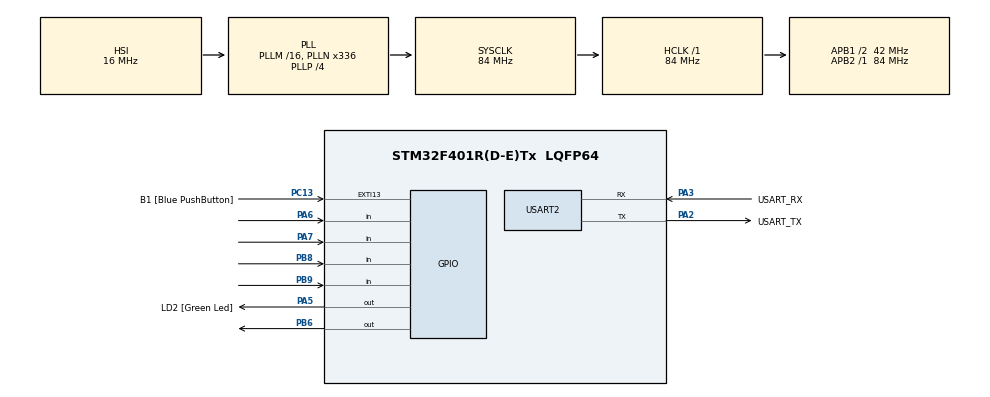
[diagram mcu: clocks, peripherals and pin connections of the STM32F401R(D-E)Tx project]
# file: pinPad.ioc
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Mcu.Family=STM32F4
Mcu.Name=STM32F401R(D-E)Tx
Mcu.Package=LQFP64
NVIC.PriorityGroup=NVIC_PRIORITYGROUP_0
PA13.GPIO_Label=TMS
PA13.Mode=Serial_Wire
PA13.Signal=SYS_JTMS-SWDIO
PA14.GPIO_Label=TCK
PA14.Mode=Serial_Wire
PA14.Signal=SYS_JTCK-SWCLK
PA2.GPIO_Label=USART_TX
PA2.GPIO_Mode=GPIO_MODE_AF_PP
PA2.GPIO_PuPd=GPIO_NOPULL
PA2.GPIO_Speed=GPIO_SPEED_FREQ_LOW
PA2.Mode=Asynchronous
PA2.Signal=USART2_TX
PA3.GPIO_Label=USART_RX
PA3.GPIO_Mode=GPIO_MODE_AF_PP
PA3.GPIO_PuPd=GPIO_NOPULL
PA3.GPIO_Speed=GPIO_SPEED_FREQ_LOW
PA3.Mode=Asynchronous
PA3.Signal=USART2_RX
PA5.GPIO_Label=LD2 [Green Led]
PA5.GPIO_Mode=GPIO_MODE_OUTPUT_PP
PA5.GPIO_PuPd=GPIO_NOPULL
PA5.GPIO_Speed=GPIO_SPEED_FREQ_LOW
PA5.Signal=GPIO_Output
PA6.GPIO_PuPd=GPIO_PULLDOWN
PA6.Signal=GPIO_Input
PA7.GPIO_PuPd=GPIO_PULLDOWN
PA7.Signal=GPIO_Input
PB3.GPIO_Label=SWO
PB3.Signal=SYS_JTDO-SWO
PB6.Signal=GPIO_Output
PB8.GPIO_PuPd=GPIO_PULLDOWN
PB8.Signal=GPIO_Input
PB9.GPIO_PuPd=GPIO_PULLDOWN
PB9.Signal=GPIO_Input
PC13-ANTI_TAMP.GPIO_Label=B1 [Blue PushButton]
PC13-ANTI_TAMP.GPIO_ModeDefaultEXTI=GPIO_MODE_IT_FALLING
PC13-ANTI_TAMP.GPIO_PuPd=GPIO_NOPULL
PC13-ANTI_TAMP.Signal=GPXTI13
PC14-OSC32_IN.Mode=LSE-External-Oscillator
PC14-OSC32_IN.Signal=RCC_OSC32_IN
PC15-OSC32_OUT.Mode=LSE-External-Oscillator
PC15-OSC32_OUT.Signal=RCC_OSC32_OUT
PH0\ -\ OSC_IN.Mode=HSE-External-Clock-Source
PH0\ -\ OSC_IN.Signal=RCC_OSC_IN
PH1\ -\ OSC_OUT.Mode=HSE-External-Clock-Source
PH1\ -\ OSC_OUT.Signal=RCC_OSC_OUT
ProjectManager.HeapSize=0x200
ProjectManager.StackSize=0x400
ProjectManager.TargetToolchain=STM32CubeIDE
RCC.48MHZClocksFreq_Value=48000000
RCC.AHBFreq_Value=84000000
RCC.APB1CLKDivider=RCC_HCLK_DIV2
RCC.APB1Freq_Value=42000000
RCC.APB1TimFreq_Value=84000000
RCC.APB2Freq_Value=84000000
RCC.APB2TimFreq_Value=84000000
RCC.CortexFreq_Value=84000000
RCC.HCLKFreq_Value=84000000
RCC.HSE_VALUE=8000000
RCC.HSI_VALUE=16000000
RCC.PLLN=336
RCC.PLLP=RCC_PLLP_DIV4
RCC.PLLQ=7
RCC.SYSCLKFreq_VALUE=84000000
RCC.SYSCLKSource=RCC_SYSCLKSOURCE_PLLCLK
RCC.VCOOutputFreq_Value=336000000
USART2.VirtualMode=VM_ASYNC
board=NUCLEO-F401RE

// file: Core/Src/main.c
/* USER CODE BEGIN Header */
/**
  ******************************************************************************
  * @file           : main.c
  * @brief          : Main program body
  ******************************************************************************
  * @attention
  * By Robin
  *
  * Copyright (c) 2024 STMicroelectronics.
  * All rights reserved.
  *
  * This software is licensed under terms that can be found in the LICENSE file
  * in the root directory of this software component.
  * If no LICENSE file comes with this software, it is provided AS-IS.
  *
  ******************************************************************************
  */
/* USER CODE END Header */
#include "main.h"
#include "stdio.h"
#include "string.h"
#include "stdbool.h"

UART_HandleTypeDef huart2;

void SystemClock_Config(void);
static void MX_GPIO_Init(void);
static void MX_USART2_UART_Init(void);

void counter();
void ledBar(int n);
_Bool password(int pin);
void turnLed(_Bool on);
void spamClick();

/* USER CODE BEGIN 0 */
int __io_putchar(int ch) {
    HAL_UART_Transmit(&huart2, (uint8_t*)&ch, 1, HAL_MAX_DELAY);  // Assuming UART2 is used
    return ch;
}
/* USER CODE END 0 */

int main(void)
{
  /* MCU Configuration--------------------------------------------------------*/

  /* Reset of all peripherals, Initializes the Flash interface and the Systick. */
  HAL_Init();
  /* Configure the system clock */
  SystemClock_Config();

  /* Initialize all configured peripherals */
  MX_GPIO_Init();
  MX_USART2_UART_Init();

  /* The actual PIN but in reverse. Must only be 1's, 2's, and 3's */
  int pin = 13221;

  /* Actual Program Run Here */
  _Bool pass = password(pin);
  //counter(buttonON, count);
  //turnLed();

  if (pass) {
	  turnLed(true);
	  printf("%d", pass);
	  counter();
  } else {
	  //Send a signal to the other STM to immediately start the speaker

	  spamClick();
  }

}

void ledBar(int n) {

	HAL_GPIO_WritePin(GPIOC, GPIO_PIN_8, GPIO_PIN_RESET); //1
	HAL_GPIO_WritePin(GPIOC, GPIO_PIN_6, GPIO_PIN_RESET); //2
	HAL_GPIO_WritePin(GPIOC, GPIO_PIN_5, GPIO_PIN_RESET); //3

	HAL_GPIO_WritePin(GPIOA, GPIO_PIN_12, GPIO_PIN_RESET); //4
	HAL_GPIO_WritePin(GPIOA, GPIO_PIN_11, GPIO_PIN_RESET); //5

	HAL_GPIO_WritePin(GPIOB, GPIO_PIN_12, GPIO_PIN_RESET); //6
	HAL_GPIO_WritePin(GPIOB, GPIO_PIN_2, GPIO_PIN_RESET); //7
	HAL_GPIO_WritePin(GPIOB, GPIO_PIN_1, GPIO_PIN_RESET); //8
	HAL_GPIO_WritePin(GPIOB, GPIO_PIN_15, GPIO_PIN_RESET); //9
	HAL_GPIO_WritePin(GPIOB, GPIO_PIN_14, GPIO_PIN_RESET); //10

	if (n > 0) {
		HAL_GPIO_WritePin(GPIOC, GPIO_PIN_8, GPIO_PIN_SET);
	} if (n > 1) {
		HAL_GPIO_WritePin(GPIOC, GPIO_PIN_6, GPIO_PIN_SET);
	} if (n > 2) {
		HAL_GPIO_WritePin(GPIOC, GPIO_PIN_5, GPIO_PIN_SET);
	} if (n > 3) {
		HAL_GPIO_WritePin(GPIOA, GPIO_PIN_12, GPIO_PIN_SET);
	} if (n > 4) {
		HAL_GPIO_WritePin(GPIOA, GPIO_PIN_11, GPIO_PIN_SET);
	} if (n > 5) {
		HAL_GPIO_WritePin(GPIOB, GPIO_PIN_12, GPIO_PIN_SET);
	} if (n > 6) {
		HAL_GPIO_WritePin(GPIOB, GPIO_PIN_2, GPIO_PIN_SET);
	} if (n > 7) {
		HAL_GPIO_WritePin(GPIOB, GPIO_PIN_1, GPIO_PIN_SET);
	} if (n > 8) {
		HAL_GPIO_WritePin(GPIOB, GPIO_PIN_15, GPIO_PIN_SET);
	} if (n > 9) {
		HAL_GPIO_WritePin(GPIOB, GPIO_PIN_14, GPIO_PIN_SET);
	}

}

/**
 * Sets the status LED to on
 * By Robin Yan.
 */
void turnLed(_Bool on) {
	if (on) {
		HAL_GPIO_WritePin(GPIOB, GPIO_PIN_13, GPIO_PIN_SET);
	} else {
		HAL_GPIO_WritePin(GPIOB, GPIO_PIN_13, GPIO_PIN_RESET);
	}

}

/**
 * Adds to or subtracts one from a counter when PB8 and PB9 receive input. The action (added/subtracted)
 * is printed followed by the current count number.
 * By Robin Yan.
 */
void counter() {
	_Bool buttonON = false;
	int count = 0;
	while (1) {
		if(HAL_GPIO_ReadPin (GPIOB, GPIO_PIN_8)) {
			if (buttonON) {
				count++;
				printf("Added: %d\n\r", count);
				buttonON = false;
			}
		} else if (HAL_GPIO_ReadPin (GPIOB, GPIO_PIN_9)) {
			if (buttonON) {
				count--;
				printf("Subtracted: %d\n\r", count);
				buttonON = false;
			}
		} else {
			if (!buttonON) {
				buttonON = true;
			}
		}

		if(count < 1) {
			count = 0;
		} else if (count > 10) {
			count = 10;
		}
		ledBar(count);
	}
}

/**
 * Fills the ledBar when the PA12 is active, and depletes the ledBar else wise
 * By Robin Yan.
 */
void spamClick() {
	int base = 50000;
	int count = base;

	while(1) {
		count--;

		if (!HAL_GPIO_ReadPin (GPIOB, GPIO_PIN_6)) {
			//count = base;
			count += 2;
		}

		if(count < 1) {
			count = 0;
		} else if (count > base) {
			count = base;
		}
		ledBar(count/(base/10));
	}

}

/**
 * Runs a loop until the inputed number sequence matches the PIN. PB8, PB9, PA6 are PIN numbers and
 * PA7 is the enter button. The loop will stop once the PIN is correct, and will print to console otherwise.
 * By Robin Yan.
 */
_Bool password(int pin) {
	int input = 0;
	_Bool correct = false;
	int waitCounter = 0;
	int waitThreshold = 200000;
	int numAttempts = 0;
	int maxAttempts = 3;

	ledBar(maxAttempts - numAttempts);

	while (!correct && maxAttempts > numAttempts) {
		if (HAL_GPIO_ReadPin (GPIOB, GPIO_PIN_8) && waitCounter > waitThreshold) {
			input *= 10;
			input += 1;
			printf("Current Input: %d\n\r", input);
			waitCounter = 0;
		}
		if (HAL_GPIO_ReadPin (GPIOB, GPIO_PIN_9) && waitCounter > waitThreshold) {
			input *= 10;
			input += 2;
			printf("Current Input: %d\n\r", input);
			waitCounter = 0;
		}
		if (HAL_GPIO_ReadPin (GPIOA, GPIO_PIN_6) && waitCounter > waitThreshold) {
			input *= 10;
			input += 3;
			printf("Current Input: %d\n\r", input);
			waitCounter = 0;
		}

		/* When enter is pressed */
		if (HAL_GPIO_ReadPin (GPIOA, GPIO_PIN_7) && waitCounter > waitThreshold) {
			waitCounter = 0;
			numAttempts++;
			if (input == pin) {
				correct = true;
				printf("Password Authentication Complete. \n\r");
			} else {
				printf("Incorrect Password. Remaining Tries: %d\n\r", maxAttempts - numAttempts);
				input = 0;
			}
			ledBar(maxAttempts - numAttempts);
		}

		/* Stop counting to save memory */
		if (waitCounter <= waitThreshold) {
			waitCounter++;
		}

	}
	//random comment
	return correct;
}

void SystemClock_Config(void)
{
  RCC_OscInitTypeDef RCC_OscInitStruct = {0};
  RCC_ClkInitTypeDef RCC_ClkInitStruct = {0};

  /** Configure the main internal regulator output voltage
  */
  __HAL_RCC_PWR_CLK_ENABLE();
  __HAL_PWR_VOLTAGESCALING_CONFIG(PWR_REGULATOR_VOLTAGE_SCALE2);

  /** Initializes the RCC Oscillators according to the specified parameters
  * in the RCC_OscInitTypeDef structure.
  */
  RCC_OscInitStruct.OscillatorType = RCC_OSCILLATORTYPE_HSI;
  RCC_OscInitStruct.HSIState = RCC_HSI_ON;
  RCC_OscInitStruct.HSICalibrationValue = RCC_HSICALIBRATION_DEFAULT;
  RCC_OscInitStruct.PLL.PLLState = RCC_PLL_ON;
  RCC_OscInitStruct.PLL.PLLSource = RCC_PLLSOURCE_HSI;
  RCC_OscInitStruct.PLL.PLLM = 16;
  RCC_OscInitStruct.PLL.PLLN = 336;
  RCC_OscInitStruct.PLL.PLLP = RCC_PLLP_DIV4;
  RCC_OscInitStruct.PLL.PLLQ = 7;
  if (HAL_RCC_OscConfig(&RCC_OscInitStruct) != HAL_OK)
  {
    Error_Handler();
  }

  /** Initializes the CPU, AHB and APB buses clocks
  */
  RCC_ClkInitStruct.ClockType = RCC_CLOCKTYPE_HCLK|RCC_CLOCKTYPE_SYSCLK
                              |RCC_CLOCKTYPE_PCLK1|RCC_CLOCKTYPE_PCLK2;
  RCC_ClkInitStruct.SYSCLKSource = RCC_SYSCLKSOURCE_PLLCLK;
  RCC_ClkInitStruct.AHBCLKDivider = RCC_SYSCLK_DIV1;
  RCC_ClkInitStruct.APB1CLKDivider = RCC_HCLK_DIV2;
  RCC_ClkInitStruct.APB2CLKDivider = RCC_HCLK_DIV1;

  if (HAL_RCC_ClockConfig(&RCC_ClkInitStruct, FLASH_LATENCY_2) != HAL_OK)
  {
    Error_Handler();
  }
}

static void MX_USART2_UART_Init(void)
{

  huart2.Instance = USART2;
  huart2.Init.BaudRate = 115200;
  huart2.Init.WordLength = UART_WORDLENGTH_8B;
  huart2.Init.StopBits = UART_STOPBITS_1;
  huart2.Init.Parity = UART_PARITY_NONE;
  huart2.Init.Mode = UART_MODE_TX_RX;
  huart2.Init.HwFlowCtl = UART_HWCONTROL_NONE;
  huart2.Init.OverSampling = UART_OVERSAMPLING_16;
  if (HAL_UART_Init(&huart2) != HAL_OK)
  {
    Error_Handler();
  }

}

static void MX_GPIO_Init(void)
{
  GPIO_InitTypeDef GPIO_InitStruct = {0};

  /* GPIO Ports Clock Enable */
  __HAL_RCC_GPIOC_CLK_ENABLE();
  __HAL_RCC_GPIOH_CLK_ENABLE();
  __HAL_RCC_GPIOA_CLK_ENABLE();
  __HAL_RCC_GPIOB_CLK_ENABLE();

  /*Configure GPIO pin Output Level */
  HAL_GPIO_WritePin(LD2_GPIO_Port, LD2_Pin, GPIO_PIN_RESET);

  /*Configure GPIO pin Output Level */
  HAL_GPIO_WritePin(GPIOB, GPIO_PIN_6, GPIO_PIN_RESET);

  /*Configure GPIO pin : B1_Pin */
  GPIO_InitStruct.Pin = B1_Pin;
  GPIO_InitStruct.Mode = GPIO_MODE_IT_FALLING;
  GPIO_InitStruct.Pull = GPIO_NOPULL;
  HAL_GPIO_Init(B1_GPIO_Port, &GPIO_InitStruct);

  /*Configure GPIO pin : LD2_Pin */
  GPIO_InitStruct.Pin = LD2_Pin;
  GPIO_InitStruct.Mode = GPIO_MODE_OUTPUT_PP;
  GPIO_InitStruct.Pull = GPIO_NOPULL;
  GPIO_InitStruct.Speed = GPIO_SPEED_FREQ_LOW;
  HAL_GPIO_Init(LD2_GPIO_Port, &GPIO_InitStruct);

  /* ----------------------------------------INPUT PINS---------------------------------------------------- */

  /*Configure GPIO pins : PA6 PA7*/
  GPIO_InitStruct.Pin = GPIO_PIN_6|GPIO_PIN_7;
  GPIO_InitStruct.Mode = GPIO_MODE_INPUT;
  GPIO_InitStruct.Pull = GPIO_PULLDOWN;
  HAL_GPIO_Init(GPIOA, &GPIO_InitStruct);

  /*Configure GPIO pins : PB8 PB9 PB6 */
  GPIO_InitStruct.Pin = GPIO_PIN_8|GPIO_PIN_9|GPIO_PIN_6;
  GPIO_InitStruct.Mode = GPIO_MODE_INPUT;
  GPIO_InitStruct.Pull = GPIO_PULLDOWN;
  HAL_GPIO_Init(GPIOB, &GPIO_InitStruct);

  /* ----------------------------------------OUTPUT PINS---------------------------------------------------- */
  	  /* LED BAR */

  /*Configure GPIO pin : PC8 PC6 PC5 */
  GPIO_InitStruct.Pin = GPIO_PIN_5|GPIO_PIN_6|GPIO_PIN_8;
  GPIO_InitStruct.Mode = GPIO_MODE_OUTPUT_PP;
  GPIO_InitStruct.Pull = GPIO_NOPULL;
  GPIO_InitStruct.Speed = GPIO_SPEED_FREQ_LOW;
  HAL_GPIO_Init(GPIOC, &GPIO_InitStruct);

  /*Configure GPIO pin : PB12 PB2 PB1 PB15 PB14 */
  GPIO_InitStruct.Pin = GPIO_PIN_12|GPIO_PIN_1|GPIO_PIN_2|GPIO_PIN_15|GPIO_PIN_14;
  GPIO_InitStruct.Mode = GPIO_MODE_OUTPUT_PP;
  GPIO_InitStruct.Pull = GPIO_NOPULL;
  GPIO_InitStruct.Speed = GPIO_SPEED_FREQ_LOW;
  HAL_GPIO_Init(GPIOB, &GPIO_InitStruct);

  /*Configure GPIO pin : PA11 PA12 */
  GPIO_InitStruct.Pin = GPIO_PIN_11|GPIO_PIN_12;
  GPIO_InitStruct.Mode = GPIO_MODE_OUTPUT_PP;
  GPIO_InitStruct.Pull = GPIO_NOPULL;
  GPIO_InitStruct.Speed = GPIO_SPEED_FREQ_LOW;
  HAL_GPIO_Init(GPIOA, &GPIO_InitStruct);

  	  /* STATUS LED */

  /*Configure GPIO pin : PB13 */
  GPIO_InitStruct.Pin = GPIO_PIN_13;
  GPIO_InitStruct.Mode = GPIO_MODE_OUTPUT_PP;
  GPIO_InitStruct.Pull = GPIO_NOPULL;
  GPIO_InitStruct.Speed = GPIO_SPEED_FREQ_LOW;
  HAL_GPIO_Init(GPIOB, &GPIO_InitStruct);

}

void Error_Handler(void)
{
  __disable_irq();
  while (1)
  {
  }
}
